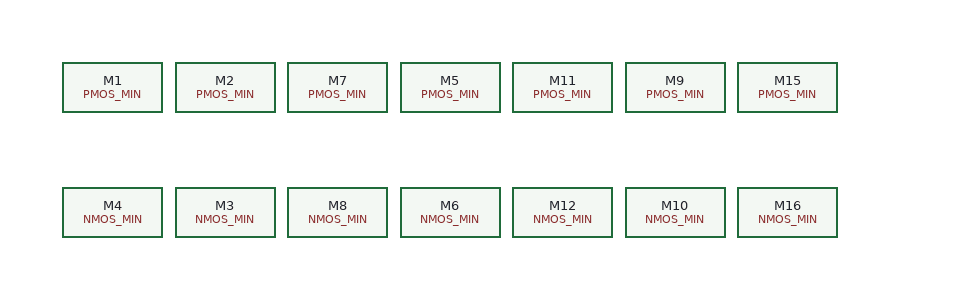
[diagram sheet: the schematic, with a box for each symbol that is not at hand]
v {xschem version=3.4.5 file_version=1.2
}
G {}
K {}
V {}
S {}
E {}
C {PMOS_MIN.sym} -10 -70 0 0 {name=M2 l=10.0U w=40.0U
}
C {NMOS_MIN.sym} -10 30 0 0 {name=M3 l=10.0U w=10.0U
}
C {PMOS_MIN.sym} -100 -70 0 0 {name=M1 l=10.0U w=40.0U
}
C {NMOS_MIN.sym} -100 30 0 0 {name=M4 l=10.0U w=10.0U
}
C {PMOS_MIN.sym} 170 -70 0 0 {name=M5 l=10.0U w=40.0U
}
C {NMOS_MIN.sym} 170 30 0 0 {name=M6 l=10.0U w=10.0U
}
C {PMOS_MIN.sym} 80 -70 0 0 {name=M7 l=10.0U w=40.0U
}
C {NMOS_MIN.sym} 80 30 0 0 {name=M8 l=10.0U w=10.0U
}
C {PMOS_MIN.sym} 350 -70 0 0 {name=M9 l=10.0U w=40.0U
}
C {NMOS_MIN.sym} 350 30 0 0 {name=M10 l=10.0U w=10.0U
}
C {PMOS_MIN.sym} 260 -70 0 0 {name=M11 l=10.0U w=40.0U
}
C {NMOS_MIN.sym} 260 30 0 0 {name=M12 l=10.0U w=10.0U
}
C {PMOS_MIN.sym} 440 -70 0 0 {name=M15 l=10.0U w=40.0U
}
C {NMOS_MIN.sym} 440 30 0 0 {name=M16 l=10.0U w=10.0U
}
